VERSION 5.8 ;
BUSBITCHARS "[]" ;
DIVIDERCHAR "/" ;
UNITS
    DATABASE MICRONS 1000 ;
END UNITS

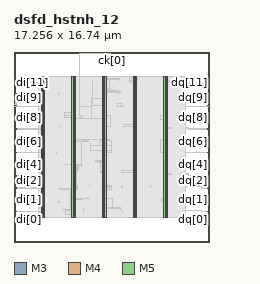
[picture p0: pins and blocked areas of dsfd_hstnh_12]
MACRO dsfd_hstnh_12
  FOREIGN dsfd_hstnh_12 0 0 ;
  CLASS BLOCK ;
  SIZE 17.256 BY 16.74 ;
  PIN ck[0]
    DIRECTION INPUT ;
    USE SIGNAL ;
    PORT
      LAYER M3 ;
        RECT  8.604 16.596 8.622 16.74 ;
    END
  END ck[0]
  PIN di[0]
    DIRECTION INPUT ;
    USE SIGNAL ;
    PORT
      LAYER M4 ;
        RECT  0 2.688 0.192 2.712 ;
    END
  END di[0]
  PIN di[10]
    DIRECTION INPUT ;
    USE SIGNAL ;
    PORT
      LAYER M4 ;
        RECT  0 13.056 0.192 13.08 ;
    END
  END di[10]
  PIN di[11]
    DIRECTION INPUT ;
    USE SIGNAL ;
    PORT
      LAYER M4 ;
        RECT  0 14.064 0.192 14.088 ;
    END
  END di[11]
  PIN di[1]
    DIRECTION INPUT ;
    USE SIGNAL ;
    PORT
      LAYER M4 ;
        RECT  0 3.744 0.192 3.768 ;
    END
  END di[1]
  PIN di[2]
    DIRECTION INPUT ;
    USE SIGNAL ;
    PORT
      LAYER M4 ;
        RECT  0 4.752 0.192 4.776 ;
    END
  END di[2]
  PIN di[3]
    DIRECTION INPUT ;
    USE SIGNAL ;
    PORT
      LAYER M4 ;
        RECT  0 5.808 0.192 5.832 ;
    END
  END di[3]
  PIN di[4]
    DIRECTION INPUT ;
    USE SIGNAL ;
    PORT
      LAYER M4 ;
        RECT  0 6.816 0.192 6.84 ;
    END
  END di[4]
  PIN di[5]
    DIRECTION INPUT ;
    USE SIGNAL ;
    PORT
      LAYER M4 ;
        RECT  0 7.872 0.192 7.896 ;
    END
  END di[5]
  PIN di[6]
    DIRECTION INPUT ;
    USE SIGNAL ;
    PORT
      LAYER M4 ;
        RECT  0 8.88 0.192 8.904 ;
    END
  END di[6]
  PIN di[7]
    DIRECTION INPUT ;
    USE SIGNAL ;
    PORT
      LAYER M4 ;
        RECT  0 9.936 0.192 9.96 ;
    END
  END di[7]
  PIN di[8]
    DIRECTION INPUT ;
    USE SIGNAL ;
    PORT
      LAYER M4 ;
        RECT  0 10.992 0.192 11.016 ;
    END
  END di[8]
  PIN di[9]
    DIRECTION INPUT ;
    USE SIGNAL ;
    PORT
      LAYER M4 ;
        RECT  0 12 0.192 12.024 ;
    END
  END di[9]
  PIN dq[0]
    DIRECTION OUTPUT ;
    USE SIGNAL ;
    PORT
      LAYER M4 ;
        RECT  17.064 2.688 17.256 2.712 ;
    END
  END dq[0]
  PIN dq[10]
    DIRECTION OUTPUT ;
    USE SIGNAL ;
    PORT
      LAYER M4 ;
        RECT  17.064 13.056 17.256 13.08 ;
    END
  END dq[10]
  PIN dq[11]
    DIRECTION OUTPUT ;
    USE SIGNAL ;
    PORT
      LAYER M4 ;
        RECT  17.064 14.064 17.256 14.088 ;
    END
  END dq[11]
  PIN dq[1]
    DIRECTION OUTPUT ;
    USE SIGNAL ;
    PORT
      LAYER M4 ;
        RECT  17.064 3.744 17.256 3.768 ;
    END
  END dq[1]
  PIN dq[2]
    DIRECTION OUTPUT ;
    USE SIGNAL ;
    PORT
      LAYER M4 ;
        RECT  17.064 4.752 17.256 4.776 ;
    END
  END dq[2]
  PIN dq[3]
    DIRECTION OUTPUT ;
    USE SIGNAL ;
    PORT
      LAYER M4 ;
        RECT  17.064 5.808 17.256 5.832 ;
    END
  END dq[3]
  PIN dq[4]
    DIRECTION OUTPUT ;
    USE SIGNAL ;
    PORT
      LAYER M4 ;
        RECT  17.064 6.816 17.256 6.84 ;
    END
  END dq[4]
  PIN dq[5]
    DIRECTION OUTPUT ;
    USE SIGNAL ;
    PORT
      LAYER M4 ;
        RECT  17.064 7.872 17.256 7.896 ;
    END
  END dq[5]
  PIN dq[6]
    DIRECTION OUTPUT ;
    USE SIGNAL ;
    PORT
      LAYER M4 ;
        RECT  17.064 8.88 17.256 8.904 ;
    END
  END dq[6]
  PIN dq[7]
    DIRECTION OUTPUT ;
    USE SIGNAL ;
    PORT
      LAYER M4 ;
        RECT  17.064 9.936 17.256 9.96 ;
    END
  END dq[7]
  PIN dq[8]
    DIRECTION OUTPUT ;
    USE SIGNAL ;
    PORT
      LAYER M4 ;
        RECT  17.064 10.992 17.256 11.016 ;
    END
  END dq[8]
  PIN dq[9]
    DIRECTION OUTPUT ;
    USE SIGNAL ;
    PORT
      LAYER M4 ;
        RECT  17.064 12 17.256 12.024 ;
    END
  END dq[9]
  PIN VDD
    DIRECTION INOUT ;
    USE POWER ;
    PORT
      LAYER M5 ;
        RECT  13.392 2.151 13.512 14.589 ;
        RECT  10.692 2.151 10.812 14.589 ;
        RECT  7.992 2.151 8.112 14.589 ;
        RECT  5.292 2.151 5.412 14.589 ;
        RECT  2.592 2.151 2.712 14.589 ;
    END
  END VDD
  PIN VSS
    DIRECTION INOUT ;
    USE GROUND ;
    PORT
      LAYER M5 ;
        RECT  13.2 2.137 13.32 14.603 ;
        RECT  10.5 2.137 10.62 14.603 ;
        RECT  7.8 2.137 7.92 14.603 ;
        RECT  5.1 2.137 5.22 14.603 ;
        RECT  2.4 2.137 2.52 14.603 ;
    END
  END VSS
  OBS
    LAYER RVTN ;
     RECT  2.16 2.16 15.066 2.295 ;
     RECT  2.16 2.565 15.066 2.835 ;
     RECT  2.16 3.105 15.066 3.375 ;
     RECT  2.16 3.645 15.066 3.915 ;
     RECT  2.16 4.185 15.066 4.455 ;
     RECT  2.16 4.725 15.066 4.995 ;
     RECT  2.16 5.265 15.066 5.535 ;
     RECT  2.16 5.805 15.066 6.075 ;
     RECT  2.16 6.345 15.066 6.615 ;
     RECT  2.16 6.885 15.066 7.155 ;
     RECT  2.16 7.425 15.066 7.695 ;
     RECT  2.16 7.965 15.066 8.235 ;
     RECT  2.16 8.505 15.066 8.775 ;
     RECT  2.16 9.045 15.066 9.315 ;
     RECT  2.16 9.585 15.066 9.855 ;
     RECT  2.16 10.125 15.066 10.395 ;
     RECT  2.16 10.665 15.066 10.935 ;
     RECT  2.16 11.205 15.066 11.475 ;
     RECT  2.16 11.745 15.066 12.015 ;
     RECT  2.16 12.285 15.066 12.555 ;
     RECT  2.16 12.825 15.066 13.095 ;
     RECT  2.16 13.365 15.066 13.635 ;
     RECT  2.16 13.905 15.066 14.175 ;
     RECT  2.16 14.445 15.066 14.58 ;
    LAYER RVTP ;
     RECT  2.16 2.295 15.066 2.565 ;
     RECT  2.16 2.835 15.066 3.105 ;
     RECT  2.16 3.375 15.066 3.645 ;
     RECT  2.16 3.915 15.066 4.185 ;
     RECT  2.16 4.455 15.066 4.725 ;
     RECT  2.16 4.995 15.066 5.265 ;
     RECT  2.16 5.535 15.066 5.805 ;
     RECT  2.16 6.075 15.066 6.345 ;
     RECT  2.16 6.615 15.066 6.885 ;
     RECT  2.16 7.155 15.066 7.425 ;
     RECT  2.16 7.695 15.066 7.965 ;
     RECT  2.16 8.235 15.066 8.505 ;
     RECT  2.16 8.775 15.066 9.045 ;
     RECT  2.16 9.315 15.066 9.585 ;
     RECT  2.16 9.855 15.066 10.125 ;
     RECT  2.16 10.395 15.066 10.665 ;
     RECT  2.16 10.935 15.066 11.205 ;
     RECT  2.16 11.475 15.066 11.745 ;
     RECT  2.16 12.015 15.066 12.285 ;
     RECT  2.16 12.555 15.066 12.825 ;
     RECT  2.16 13.095 15.066 13.365 ;
     RECT  2.16 13.635 15.066 13.905 ;
     RECT  2.16 14.175 15.066 14.445 ;
    LAYER M1 ;
     RECT  2.16 2.151 15.066 14.589 ;
    LAYER M2 ;
     RECT  0.031 11.952 2.16 11.97 ;
     RECT  8.419 16.578 8.627 16.596 ;
     RECT  2.16 2.151 15.066 14.589 ;
     RECT  15.066 5.976 15.395 5.994 ;
     RECT  15.066 10.026 15.395 10.044 ;
     RECT  15.066 13.068 15.395 13.086 ;
     RECT  15.066 14.076 15.395 14.094 ;
     RECT  15.066 2.736 16.547 2.754 ;
     RECT  15.066 3.816 16.547 3.834 ;
     RECT  15.066 4.896 16.547 4.914 ;
     RECT  15.066 6.786 16.547 6.804 ;
     RECT  15.066 7.866 16.547 7.884 ;
     RECT  15.066 8.946 16.547 8.964 ;
     RECT  15.066 11.106 16.547 11.124 ;
     RECT  15.066 11.916 17.023 11.934 ;
     RECT  17.023 11.916 17.123 12.006 ;
    LAYER M3 ;
     RECT  2.415 2.143 2.505 2.413 ;
     RECT  5.115 2.143 5.205 2.413 ;
     RECT  7.815 2.143 7.905 2.413 ;
     RECT  10.515 2.143 10.605 2.413 ;
     RECT  13.215 2.143 13.305 2.413 ;
     RECT  5.115 2.413 5.397 2.461 ;
     RECT  2.415 2.413 2.697 2.605 ;
     RECT  2.304 2.605 2.697 2.717 ;
     RECT  4.5 2.461 5.397 2.759 ;
     RECT  9.576 2.641 9.594 2.759 ;
     RECT  16.524 2.683 16.542 2.759 ;
     RECT  4.356 2.767 4.374 2.861 ;
     RECT  7.815 2.413 8.097 2.911 ;
     RECT  9.36 2.803 9.378 2.911 ;
     RECT  7.815 2.911 9.378 3.029 ;
     RECT  6.12 2.731 6.138 3.065 ;
     RECT  7.815 3.029 9.018 3.065 ;
     RECT  13.215 2.413 13.497 3.541 ;
     RECT  5.115 2.759 5.397 3.547 ;
     RECT  3.96 3.451 3.978 3.569 ;
     RECT  5.04 3.547 5.397 3.605 ;
     RECT  2.415 2.717 2.697 3.685 ;
     RECT  5.115 3.605 5.397 3.721 ;
     RECT  2.304 3.685 2.697 3.773 ;
     RECT  5.115 3.721 6.03 3.811 ;
     RECT  7.815 3.065 8.694 3.839 ;
     RECT  16.524 3.739 16.542 3.839 ;
     RECT  5.115 3.811 6.534 3.875 ;
     RECT  7.815 3.839 8.19 3.875 ;
     RECT  12.996 3.541 13.497 3.875 ;
     RECT  6.516 3.875 6.534 3.947 ;
     RECT  7.815 3.875 8.097 4.621 ;
     RECT  3.996 4.621 4.014 4.651 ;
     RECT  5.115 3.875 5.397 4.651 ;
     RECT  3.996 4.651 5.397 4.691 ;
     RECT  2.415 3.773 2.697 4.747 ;
     RECT  2.34 4.747 2.697 4.793 ;
     RECT  3.996 4.691 4.014 4.793 ;
     RECT  5.115 4.691 5.397 4.801 ;
     RECT  7.815 4.621 8.622 4.801 ;
     RECT  7.74 4.801 8.622 4.919 ;
     RECT  9.504 4.801 9.522 4.919 ;
     RECT  16.524 4.747 16.542 4.919 ;
     RECT  5.115 4.801 5.634 4.955 ;
     RECT  7.815 4.919 8.622 4.955 ;
     RECT  11.988 4.801 12.006 4.955 ;
     RECT  6.66 4.891 6.678 4.991 ;
     RECT  2.415 4.793 2.697 5.803 ;
     RECT  13.215 3.875 13.497 5.971 ;
     RECT  15.372 5.803 15.39 5.999 ;
     RECT  5.115 4.955 5.397 6.007 ;
     RECT  2.304 5.803 2.697 6.035 ;
     RECT  13.215 5.971 13.914 6.071 ;
     RECT  10.515 2.413 10.797 6.115 ;
     RECT  7.815 4.955 8.097 6.151 ;
     RECT  10.44 6.115 10.797 6.151 ;
     RECT  7.596 6.151 8.097 6.241 ;
     RECT  9.432 6.151 10.797 6.269 ;
     RECT  10.008 6.269 10.797 6.305 ;
     RECT  5.115 6.007 5.526 6.385 ;
     RECT  5.115 6.385 5.706 6.781 ;
     RECT  2.415 6.035 2.697 6.808 ;
     RECT  2.412 6.808 2.697 6.845 ;
     RECT  16.524 6.781 16.542 6.845 ;
     RECT  4.356 6.811 4.374 6.851 ;
     RECT  7.596 6.241 8.19 6.961 ;
     RECT  7.416 6.961 8.19 7.051 ;
     RECT  7.2 7.051 8.19 7.079 ;
     RECT  5.115 6.781 5.922 7.115 ;
     RECT  7.2 7.079 8.154 7.151 ;
     RECT  13.215 6.071 13.497 7.861 ;
     RECT  2.415 6.845 2.697 7.867 ;
     RECT  3.744 7.771 3.762 7.889 ;
     RECT  5.115 7.115 5.778 7.889 ;
     RECT  7.815 7.151 8.154 7.897 ;
     RECT  16.524 7.861 16.542 7.901 ;
     RECT  2.304 7.867 2.697 7.925 ;
     RECT  5.115 7.889 5.598 7.925 ;
     RECT  7.815 7.897 8.586 8.041 ;
     RECT  6.732 8.041 8.586 8.465 ;
     RECT  3.528 8.581 3.546 8.699 ;
     RECT  6.732 8.465 6.75 8.699 ;
     RECT  5.115 7.925 5.397 8.815 ;
     RECT  5.115 8.815 5.778 8.851 ;
     RECT  5.115 8.851 6.606 8.909 ;
     RECT  7.524 8.465 8.586 8.969 ;
     RECT  16.524 8.875 16.542 8.969 ;
     RECT  7.524 8.969 8.37 9.005 ;
     RECT  12.924 7.861 13.497 9.005 ;
     RECT  5.115 8.909 5.778 9.101 ;
     RECT  6.588 8.909 6.606 9.101 ;
     RECT  7.74 9.005 8.097 9.275 ;
     RECT  2.415 7.925 2.697 9.931 ;
     RECT  13.215 9.005 13.497 10.021 ;
     RECT  7.815 9.275 8.097 10.027 ;
     RECT  15.372 9.931 15.39 10.049 ;
     RECT  2.304 9.931 2.697 10.085 ;
     RECT  7.092 10.027 8.097 10.085 ;
     RECT  13.215 10.021 13.806 10.121 ;
     RECT  10.515 6.305 10.797 10.165 ;
     RECT  7.815 10.085 8.097 10.201 ;
     RECT  10.26 10.165 10.797 10.201 ;
     RECT  3.996 10.057 4.014 10.229 ;
     RECT  9.684 10.201 10.797 10.319 ;
     RECT  10.116 10.319 10.797 10.355 ;
     RECT  13.215 10.121 13.497 10.831 ;
     RECT  6.48 10.831 6.498 10.843 ;
     RECT  6.192 10.843 6.498 10.895 ;
     RECT  2.415 10.085 2.697 10.975 ;
     RECT  5.115 9.101 5.397 10.975 ;
     RECT  4.464 10.975 5.397 11.011 ;
     RECT  2.304 10.975 2.697 11.021 ;
     RECT  7.815 10.201 8.514 11.129 ;
     RECT  16.524 10.987 16.542 11.129 ;
     RECT  4.464 11.011 6.03 11.165 ;
     RECT  7.815 11.129 8.298 11.165 ;
     RECT  12.924 10.831 13.497 11.165 ;
     RECT  6.804 11.101 6.822 11.201 ;
     RECT  4.464 11.165 5.634 11.453 ;
     RECT  7.815 11.165 8.097 11.933 ;
     RECT  9.612 11.911 9.63 11.933 ;
     RECT  9.144 11.933 9.63 11.975 ;
     RECT  5.115 11.453 5.634 11.981 ;
     RECT  17.1 11.911 17.118 11.983 ;
     RECT  0.036 11.933 0.054 11.995 ;
     RECT  17.028 11.983 17.118 12.011 ;
     RECT  17.028 12.011 17.046 12.029 ;
     RECT  0.036 11.995 0.234 12.125 ;
     RECT  9.144 11.975 9.45 12.209 ;
     RECT  7.2 11.933 8.097 12.245 ;
     RECT  9.36 12.209 9.378 12.245 ;
     RECT  7.815 12.245 8.097 12.991 ;
     RECT  2.415 11.021 2.697 13.027 ;
     RECT  2.412 13.027 2.697 13.085 ;
     RECT  15.372 13.051 15.39 13.091 ;
     RECT  9.216 12.991 9.234 13.135 ;
     RECT  7.815 12.991 8.154 13.171 ;
     RECT  9.216 13.135 9.414 13.171 ;
     RECT  3.888 13.027 3.906 13.199 ;
     RECT  7.815 13.171 9.414 13.289 ;
     RECT  7.815 13.289 9.234 13.325 ;
     RECT  7.815 13.325 8.514 13.559 ;
     RECT  2.415 13.085 2.697 14.059 ;
     RECT  10.515 10.355 10.797 14.071 ;
     RECT  13.215 11.165 13.497 14.071 ;
     RECT  6.876 12.571 6.894 14.099 ;
     RECT  15.372 14.059 15.39 14.099 ;
     RECT  2.304 14.059 2.697 14.135 ;
     RECT  10.188 14.071 10.797 14.215 ;
     RECT  13.215 14.071 14.094 14.243 ;
     RECT  2.415 14.135 2.697 14.327 ;
     RECT  5.115 11.981 5.397 14.327 ;
     RECT  13.215 14.243 13.497 14.327 ;
     RECT  7.815 13.559 8.406 14.341 ;
     RECT  9.288 14.251 9.306 14.341 ;
     RECT  7.815 14.341 9.306 14.369 ;
     RECT  10.188 14.215 10.854 14.369 ;
     RECT  7.815 14.369 8.874 14.405 ;
     RECT  10.188 14.369 10.605 14.405 ;
     RECT  8.856 14.405 8.874 14.441 ;
     RECT  2.415 14.327 2.505 14.597 ;
     RECT  5.115 14.327 5.205 14.597 ;
     RECT  7.815 14.405 7.905 14.597 ;
     RECT  10.515 14.405 10.605 14.597 ;
     RECT  13.215 14.327 13.305 14.597 ;
     RECT  8.424 16.573 8.622 16.62 ;
     RECT  8.424 16.62 8.442 16.637 ;
    LAYER M4 ;
     RECT  0.025 12.096 0.156 12.12 ;
     RECT  0.156 12 0.245 13.08 ;
     RECT  0.156 2.688 2.408 2.712 ;
     RECT  0.156 3.744 2.408 3.768 ;
     RECT  0.156 4.752 2.408 4.776 ;
     RECT  0.156 5.808 2.408 5.832 ;
     RECT  0.156 6.816 2.408 6.84 ;
     RECT  0.156 7.872 2.408 7.896 ;
     RECT  0.156 8.88 2.408 8.904 ;
     RECT  0.156 9.936 2.408 9.96 ;
     RECT  0.156 10.992 2.408 11.016 ;
     RECT  0.245 13.056 2.408 13.08 ;
     RECT  0.156 14.064 2.408 14.088 ;
     RECT  2.408 2.148 2.512 14.592 ;
     RECT  2.512 2.418 2.704 14.322 ;
     RECT  4.345 2.832 4.981 2.856 ;
     RECT  4.981 2.832 5.108 3.576 ;
     RECT  4.669 4.656 5.108 4.68 ;
     RECT  4.345 6.816 5.108 6.84 ;
     RECT  4.453 11.424 5.108 11.448 ;
     RECT  5.108 2.148 5.212 14.592 ;
     RECT  5.212 2.418 5.404 14.322 ;
     RECT  5.404 4.656 5.555 4.68 ;
     RECT  5.404 6.24 5.581 6.84 ;
     RECT  5.404 7.872 5.609 7.896 ;
     RECT  5.404 10.848 5.645 11.976 ;
     RECT  5.581 6.816 5.939 6.84 ;
     RECT  5.404 8.88 6.083 9.096 ;
     RECT  6.083 9.072 6.805 9.096 ;
     RECT  5.645 10.848 6.805 10.872 ;
     RECT  5.645 11.952 6.865 11.976 ;
     RECT  6.805 9.072 7.808 10.872 ;
     RECT  6.865 11.952 7.808 12.6 ;
     RECT  7.808 2.148 7.912 14.592 ;
     RECT  7.912 2.418 8.104 14.322 ;
     RECT  5.749 16.608 8.453 16.632 ;
     RECT  10.508 2.148 10.612 14.592 ;
     RECT  10.612 2.418 10.804 14.322 ;
     RECT  13.208 2.148 13.312 14.592 ;
     RECT  13.312 2.418 13.504 14.322 ;
     RECT  16.513 2.688 17.1 2.712 ;
     RECT  16.513 3.744 17.1 3.768 ;
     RECT  16.513 4.752 17.1 4.776 ;
     RECT  15.361 5.808 17.1 5.832 ;
     RECT  16.513 6.816 17.1 6.84 ;
     RECT  16.513 7.872 17.1 7.896 ;
     RECT  16.513 8.88 17.1 8.904 ;
     RECT  15.361 9.936 17.1 9.96 ;
     RECT  16.513 10.992 17.1 11.016 ;
     RECT  17.017 12 17.1 12.024 ;
     RECT  15.361 13.056 17.1 13.08 ;
     RECT  15.361 14.064 17.1 14.088 ;
    LAYER M5 ;
     RECT  2.4 2.137 2.52 2.151 ;
     RECT  5.1 2.137 5.22 2.151 ;
     RECT  7.8 2.137 7.92 2.151 ;
     RECT  10.5 2.137 10.62 2.151 ;
     RECT  13.2 2.137 13.32 2.151 ;
     RECT  5.1 2.151 5.412 2.821 ;
     RECT  4.992 2.821 5.412 4.645 ;
     RECT  4.992 4.645 5.544 4.691 ;
     RECT  5.1 4.691 5.544 6.805 ;
     RECT  5.1 6.805 5.928 8.869 ;
     RECT  5.1 8.869 6.072 9.061 ;
     RECT  7.8 2.151 8.112 9.061 ;
     RECT  5.1 9.061 8.112 10.883 ;
     RECT  6.816 10.883 8.112 11.987 ;
     RECT  6.912 11.987 8.112 12.611 ;
     RECT  2.4 2.151 2.712 14.589 ;
     RECT  7.8 12.611 8.112 14.589 ;
     RECT  10.5 2.151 10.812 14.589 ;
     RECT  13.2 2.151 13.512 14.589 ;
     RECT  2.4 14.589 2.52 14.603 ;
     RECT  5.1 10.883 5.784 14.603 ;
     RECT  7.8 14.589 7.92 14.603 ;
     RECT  10.5 14.589 10.62 14.603 ;
     RECT  13.2 14.589 13.32 14.603 ;
     RECT  5.76 14.603 5.784 16.643 ;
  END
END dsfd_hstnh_12
END LIBRARY
